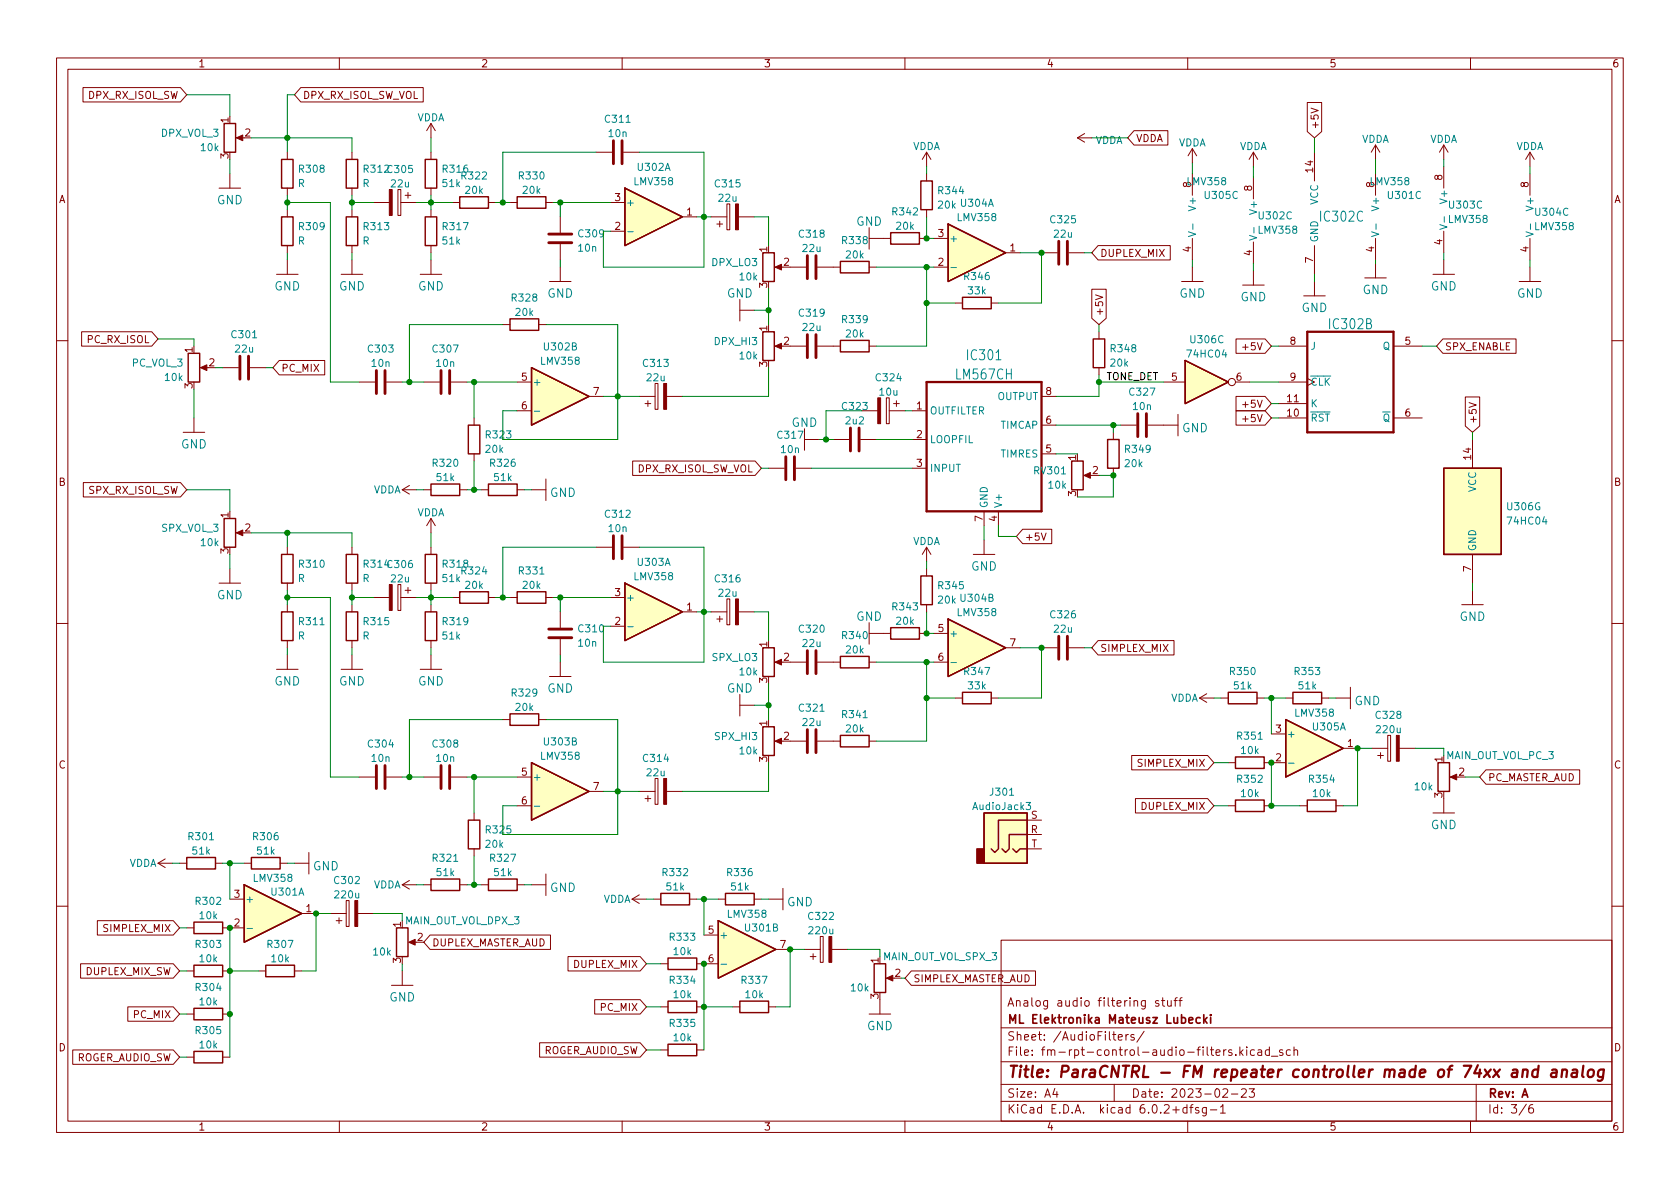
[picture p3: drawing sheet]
<svg xmlns="http://www.w3.org/2000/svg" width="297mm" height="210mm" viewBox="0 0 297 210" stroke-linecap="round" stroke-linejoin="round" font-family="sans-serif">
<defs><g id="words">
<text font-size="2.8" fill="#840000" x="178" y="190.6">Title: ParaCNTRL - FM repeater controller made of 74xx and analog</text>
<g font-size="2.5" fill="#008484">
<text x="233.6" y="39.2">IC302C</text>
<text x="235.2" y="58.2">IC302B</text>
<text x="171.2" y="63.7">IC301</text>
<text x="169.2" y="67.1">LM567CH</text>
</g>
<g font-size="2.1" fill="#008484">
<text x="38.3" y="36.1">GND</text>
<text x="151.4" y="39.9">GND</text>
<text x="48.5" y="51.4">GND</text>
<text x="59.9" y="51.4">GND</text>
<text x="73.9" y="51.4">GND</text>
<text x="96.7" y="52.6">GND</text>
<text x="128.5" y="52.6">GND</text>
<text x="208.5" y="52.6">GND</text>
<text x="219.3" y="53.3">GND</text>
<text x="240.9" y="52">GND</text>
<text x="253" y="51.4">GND</text>
<text x="268.2" y="52.6">GND</text>
<text x="230.1" y="55.2">GND</text>
<text x="139.9" y="75.5">GND</text>
<text x="209" y="76.4">GND</text>
<text x="32" y="79.3">GND</text>
<text x="97.2" y="87.9">GND</text>
<text x="171.7" y="100.9">GND</text>
<text x="38.3" y="106">GND</text>
<text x="151.4" y="109.8">GND</text>
<text x="258" y="109.8">GND</text>
<text x="48.5" y="121.2">GND</text>
<text x="59.9" y="121.2">GND</text>
<text x="73.9" y="121.2">GND</text>
<text x="96.7" y="122.5">GND</text>
<text x="128.5" y="122.5">GND</text>
<text x="239.5" y="124.7">GND</text>
<text x="253" y="146.6">GND</text>
<text x="55.3" y="153.9">GND</text>
<text x="97.2" y="157.7">GND</text>
<text x="139.1" y="160.3">GND</text>
<text x="68.8" y="177.1">GND</text>
<text x="153.3" y="182.2">GND</text>
</g>
<g font-size="2.1" fill="#840000">
<text x="178" y="178">Analog audio filtering stuff</text>
<text x="178" y="184">Sheet: /AudioFilters/</text>
<text x="178" y="181">ML Elektronika Mateusz Lubecki</text>
<text x="178" y="186.7">File: fm-rpt-control-audio-filters.kicad_sch</text>
<text x="178" y="196.9">KiCad E.D.A. kicad 6.0.2+dfsg-1</text>
<text x="178" y="194.1">Size: A4</text>
<text x="200" y="194.1">Date: 2023-02-23</text>
<text x="263" y="194.1">Rev: A</text>
<text x="263" y="196.9">Id: 3/6</text>
</g>
<g font-size="1.8" fill="#840000">
<text x="35" y="11.9">1</text>
<text x="85" y="11.9">2</text>
<text x="135" y="11.9">3</text>
<text x="185" y="11.9">4</text>
<text x="235" y="11.9">5</text>
<text x="285" y="11.9">6</text>
<text x="15.6" y="17.5">DPX_RX_ISOL_SW</text>
<text x="53.5" y="17.5">DPX_RX_ISOL_SW_VOL</text>
<text x="40.4" y="21.7" transform="rotate(-90 40.4 21.7)">1</text>
<text x="233.1" y="22.9" transform="rotate(-90 233.1 22.9)">+5V</text>
<text x="40.4" y="28" transform="rotate(-90 40.4 28)">3</text>
<text x="43.3" y="24.1">2</text>
<text x="200.8" y="25.1">VDDA</text>
<text x="10.3" y="35.9">A</text>
<text x="108.7" y="35.6">3</text>
<text x="210.6" y="33.1" transform="rotate(-90 210.6 33.1)">8</text>
<text x="221.4" y="33.8" transform="rotate(-90 221.4 33.8)">8</text>
<text x="232.2" y="30.4" transform="rotate(-90 232.2 30.4)">14</text>
<text x="243" y="33.1" transform="rotate(-90 243 33.1)">8</text>
<text x="255" y="31.9" transform="rotate(-90 255 31.9)">8</text>
<text x="270.3" y="33.1" transform="rotate(-90 270.3 33.1)">8</text>
<text x="285.3" y="35.9">A</text>
<text x="108.7" y="40.6">2</text>
<text x="121.4" y="38.1">1</text>
<text x="165.9" y="41.9">3</text>
<text x="135.6" y="44.6" transform="rotate(-90 135.6 44.6)">1</text>
<text x="138.6" y="47">2</text>
<text x="165.9" y="47">2</text>
<text x="178.6" y="44.4">1</text>
<text x="194.5" y="45.4">DUPLEX_MIX</text>
<text x="210.6" y="44.6" transform="rotate(-90 210.6 44.6)">4</text>
<text x="221.4" y="45.2" transform="rotate(-90 221.4 45.2)">4</text>
<text x="232.2" y="46.5" transform="rotate(-90 232.2 46.5)">7</text>
<text x="243" y="44.6" transform="rotate(-90 243 44.6)">4</text>
<text x="255" y="43.3" transform="rotate(-90 255 43.3)">4</text>
<text x="270.3" y="44.6" transform="rotate(-90 270.3 44.6)">4</text>
<text x="135.6" y="50.9" transform="rotate(-90 135.6 50.9)">3</text>
<text x="135.6" y="58.5" transform="rotate(-90 135.6 58.5)">1</text>
<text x="195" y="56" transform="rotate(-90 195 56)">+5V</text>
<text x="15.5" y="60.7">PC_RX_ISOL</text>
<text x="34" y="62.3" transform="rotate(-90 34 62.3)">1</text>
<text x="37" y="64.8">2</text>
<text x="49.7" y="65.7">PC_MIX</text>
<text x="135.6" y="64.9" transform="rotate(-90 135.6 64.9)">3</text>
<text x="138.6" y="61">2</text>
<text x="220.2" y="61.9">+5V</text>
<text x="228.1" y="61">8</text>
<text x="248.4" y="61">5</text>
<text x="255.4" y="61.9">SPX_ENABLE</text>
<text x="34" y="68.7" transform="rotate(-90 34 68.7)">3</text>
<text x="92.2" y="67.3">5</text>
<text x="104.9" y="69.8">7</text>
<text x="184.9" y="69.8">8</text>
<text x="207.2" y="67.3">5</text>
<text x="218.6" y="67.3">6</text>
<text x="227.6" y="71.1">11</text>
<text x="228.1" y="67.3">9</text>
<text x="92.2" y="72.4">6</text>
<text x="162.1" y="72.4">1</text>
<text x="162.1" y="77.5">2</text>
<text x="184.9" y="74.9">6</text>
<text x="220.2" y="74.6">+5V</text>
<text x="220.2" y="72.1">+5V</text>
<text x="227.6" y="73.7">10</text>
<text x="248.4" y="73.7">6</text>
<text x="261.1" y="75" transform="rotate(-90 261.1 75)">+5V</text>
<text x="112.5" y="83.5">DPX_RX_ISOL_SW_VOL</text>
<text x="162.1" y="82.5">3</text>
<text x="184.9" y="80">5</text>
<text x="190.2" y="81.4" transform="rotate(-90 190.2 81.4)">1</text>
<text x="193.2" y="83.8">2</text>
<text x="260.1" y="81.2" transform="rotate(-90 260.1 81.2)">14</text>
<text x="10.3" y="85.9">B</text>
<text x="15.7" y="87.3">SPX_RX_ISOL_SW</text>
<text x="190.2" y="87.7" transform="rotate(-90 190.2 87.7)">3</text>
<text x="285.3" y="85.9">B</text>
<text x="40.4" y="91.5" transform="rotate(-90 40.4 91.5)">1</text>
<text x="43.3" y="94">2</text>
<text x="173.7" y="92.2" transform="rotate(-90 173.7 92.2)">7</text>
<text x="176.3" y="92.2" transform="rotate(-90 176.3 92.2)">4</text>
<text x="181.1" y="95.6">+5V</text>
<text x="40.4" y="97.9" transform="rotate(-90 40.4 97.9)">3</text>
<text x="260.1" y="101.1" transform="rotate(-90 260.1 101.1)">7</text>
<text x="108.7" y="105.4">3</text>
<text x="121.4" y="107.9">1</text>
<text x="108.7" y="110.5">2</text>
<text x="165.9" y="111.8">5</text>
<text x="135.6" y="114.4" transform="rotate(-90 135.6 114.4)">1</text>
<text x="138.6" y="116.8">2</text>
<text x="165.9" y="116.8">6</text>
<text x="178.6" y="114.3">7</text>
<text x="194.5" y="115.3">SIMPLEX_MIX</text>
<text x="135.6" y="120.8" transform="rotate(-90 135.6 120.8)">3</text>
<text x="135.6" y="128.4" transform="rotate(-90 135.6 128.4)">1</text>
<text x="138.6" y="130.8">2</text>
<text x="225.6" y="129.5">3</text>
<text x="10.3" y="135.9">C</text>
<text x="92.2" y="137.2">5</text>
<text x="135.6" y="134.7" transform="rotate(-90 135.6 134.7)">3</text>
<text x="201.3" y="135.6">SIMPLEX_MIX</text>
<text x="225.6" y="134.6">2</text>
<text x="238.3" y="132.1">1</text>
<text x="255" y="134.7" transform="rotate(-90 255 134.7)">1</text>
<text x="258" y="137.2">2</text>
<text x="285.3" y="135.9">C</text>
<text x="92.2" y="142.2">6</text>
<text x="104.9" y="139.7">7</text>
<text x="201.9" y="143.2">DUPLEX_MIX</text>
<text x="255" y="141.1" transform="rotate(-90 255 141.1)">3</text>
<text x="263.1" y="138.1">PC_MASTER_AUD</text>
<text x="182.2" y="147.3">R</text>
<text x="182.3" y="144.8">S</text>
<text x="182.3" y="149.9">T</text>
<text x="41.4" y="158.7">3</text>
<text x="54.1" y="161.3">1</text>
<text x="18.4" y="164.8">SIMPLEX_MIX</text>
<text x="41.4" y="163.8">2</text>
<text x="70.9" y="163.9" transform="rotate(-90 70.9 163.9)">1</text>
<text x="73.8" y="166.4">2</text>
<text x="76.4" y="167.3">DUPLEX_MASTER_AUD</text>
<text x="125.2" y="165.1">5</text>
<text x="137.9" y="167.6">7</text>
<text x="15.2" y="172.4">DUPLEX_MIX_SW</text>
<text x="70.9" y="170.3" transform="rotate(-90 70.9 170.3)">3</text>
<text x="101.6" y="171.2">DUPLEX_MIX</text>
<text x="125.2" y="170.2">6</text>
<text x="155.3" y="170.3" transform="rotate(-90 155.3 170.3)">1</text>
<text x="158.3" y="172.7">2</text>
<text x="161.4" y="173.7">SIMPLEX_MASTER_AUD</text>
<text x="106.3" y="178.8">PC_MIX</text>
<text x="155.3" y="176.6" transform="rotate(-90 155.3 176.6)">3</text>
<text x="10.3" y="185.9">D</text>
<text x="23.7" y="180">PC_MIX</text>
<text x="285.3" y="185.9">D</text>
<text x="13.3" y="187.7">ROGER_AUDIO_SW</text>
<text x="95.9" y="186.4">ROGER_AUDIO_SW</text>
<text x="35" y="199.9">1</text>
<text x="85" y="199.9">2</text>
<text x="135" y="199.9">3</text>
<text x="185" y="199.9">4</text>
<text x="235" y="199.9">5</text>
<text x="285" y="199.9">6</text>
</g>
<g font-size="1.8" fill="#008484">
<text x="73.7" y="21.4">VDDA</text>
<text x="107.1" y="21.7">C311</text>
<text x="28.5" y="24.2">DPX_VOL_3</text>
<text x="35.6" y="26.7">10k</text>
<text x="107.7" y="24.2">10n</text>
<text x="161.3" y="26.5">VDDA</text>
<text x="193.6" y="25.4">VDDA</text>
<text x="208.3" y="25.9">VDDA</text>
<text x="219.1" y="26.5">VDDA</text>
<text x="240.7" y="25.2">VDDA</text>
<text x="252.8" y="25.2">VDDA</text>
<text x="268" y="26.5">VDDA</text>
<text x="52.7" y="33.1">R</text>
<text x="53" y="30.5">R308</text>
<text x="64.1" y="33.1">R</text>
<text x="64.4" y="30.5">R312C305</text>
<text x="69.2" y="33.1">22u</text>
<text x="78.3" y="33.1">51k</text>
<text x="78.4" y="30.5">R316</text>
<text x="81.7" y="31.7">R322</text>
<text x="82.3" y="34.3">20k</text>
<text x="91.9" y="31.7">R330</text>
<text x="92.5" y="34.3">20k</text>
<text x="112.2" y="32.7">LMV358</text>
<text x="112.8" y="30.2">U302A</text>
<text x="126.5" y="33.1">C315</text>
<text x="127.1" y="35.7">22u</text>
<text x="166" y="34.3">R344</text>
<text x="210" y="32.7">LMV358</text>
<text x="213.1" y="35.2">U305C</text>
<text x="242.4" y="32.7">LMV358</text>
<text x="245.5" y="35.2">U301C</text>
<text x="255.9" y="35.6" transform="rotate(-90 255.9 35.6)">V+</text>
<text x="53" y="40.7">R309</text>
<text x="64.4" y="40.7">R313</text>
<text x="78.4" y="40.7">R317</text>
<text x="102.4" y="42">C309</text>
<text x="110.6" y="36.4">+</text>
<text x="157.9" y="38.1">R342</text>
<text x="158.5" y="40.6">20k</text>
<text x="165.9" y="36.9">20k U304A</text>
<text x="169.4" y="39.1">LMV358</text>
<text x="185.8" y="39.5">C325</text>
<text x="211.5" y="36.9" transform="rotate(-90 211.5 36.9)">V+</text>
<text x="222.2" y="37.5" transform="rotate(-90 222.2 37.5)">V+</text>
<text x="222.6" y="41.3">LMV358</text>
<text x="222.7" y="38.8">U302C</text>
<text x="233" y="36.2" transform="rotate(-90 233 36.2)">VCC</text>
<text x="243.8" y="36.9" transform="rotate(-90 243.8 36.9)">V+</text>
<text x="256.2" y="39.4">LMV358</text>
<text x="256.3" y="36.9">U303C</text>
<text x="271.1" y="36.9" transform="rotate(-90 271.1 36.9)">V+</text>
<text x="271.5" y="40.7">LMV358</text>
<text x="271.6" y="38.1">U304C</text>
<text x="52.7" y="43.2">R</text>
<text x="64.1" y="43.2">R</text>
<text x="78.3" y="43.2">51k</text>
<text x="102.3" y="44.5">10n</text>
<text x="125.9" y="47">DPX_LO3</text>
<text x="141.4" y="42">C318</text>
<text x="142" y="44.6">22u</text>
<text x="149" y="43.2">R338</text>
<text x="149.7" y="45.7">20k</text>
<text x="167.8" y="42.8">+</text>
<text x="186.4" y="42">22u</text>
<text x="233" y="42.9" transform="rotate(-90 233 42.9)">GND</text>
<text x="90.6" y="53.3">R328</text>
<text x="130.8" y="49.6">10k</text>
<text x="170.6" y="49.5">R346</text>
<text x="171.2" y="52">33k</text>
<text x="41.1" y="59.8">C301</text>
<text x="91.2" y="55.9">20k</text>
<text x="141.4" y="56">C319</text>
<text x="142" y="58.5">22u</text>
<text x="149" y="57.1">R339</text>
<text x="149.7" y="59.7">20k</text>
<text x="23.3" y="64.8">PC_VOL_3</text>
<text x="41.7" y="62.3">22u</text>
<text x="65.2" y="62.3">C303</text>
<text x="65.8" y="64.9">10n</text>
<text x="76.6" y="62.3">C307</text>
<text x="77.2" y="64.9">10n</text>
<text x="95.7" y="64.5">LMV358</text>
<text x="96.3" y="62">U302B</text>
<text x="113.8" y="64.9">C313</text>
<text x="126.4" y="61">DPX_HI3</text>
<text x="130.8" y="63.5">10k</text>
<text x="196.4" y="64.8">20k</text>
<text x="196.5" y="62.3">R348</text>
<text x="210.1" y="63.2">74HC04</text>
<text x="210.6" y="60.7">U306C</text>
<text x="231.6" y="61.8">J</text>
<text x="244.5" y="61.8">Q</text>
<text x="29.2" y="67.4">10k</text>
<text x="94.1" y="68.2">+</text>
<text x="114.4" y="67.4">22u</text>
<text x="155" y="67.4">C324</text>
<text x="155.6" y="70">10u</text>
<text x="176.4" y="70.7">OUTPUT</text>
<text x="199.8" y="70">C327</text>
<text x="231.6" y="68.2">~{CLK}</text>
<text x="86" y="77.5">R323</text>
<text x="137.6" y="77.6">C317</text>
<text x="149" y="72.5">C323</text>
<text x="149.6" y="75">2u2</text>
<text x="164.3" y="73.3">OUTFILTER</text>
<text x="176.9" y="75.8">TIMCAP</text>
<text x="200.4" y="72.5">10n</text>
<text x="231.6" y="74.5">~{RST}</text>
<text x="231.6" y="72">K</text>
<text x="243.1" y="74.5">~{Q}</text>
<text x="76.6" y="82.5">R320</text>
<text x="85.9" y="80.1">20k</text>
<text x="86.8" y="82.5">R326</text>
<text x="138.2" y="80.1">10n</text>
<text x="164.3" y="78.4">LOOPFIL</text>
<text x="164.3" y="83.4">INPUT</text>
<text x="177" y="80.9">TIMRES</text>
<text x="182.9" y="83.9">RV301</text>
<text x="199" y="82.6">20k</text>
<text x="199" y="80.1">R349</text>
<text x="66" y="87.2">VDDA</text>
<text x="77.3" y="85.1">51k</text>
<text x="87.4" y="85.1">51k</text>
<text x="174.6" y="89.9" transform="rotate(-90 174.6 89.9)">GND</text>
<text x="177.2" y="89.9" transform="rotate(-90 177.2 89.9)">V+</text>
<text x="185.4" y="86.4">10k</text>
<text x="261" y="87" transform="rotate(-90 261 87)">VCC</text>
<text x="28.6" y="94">SPX_VOL_3</text>
<text x="73.7" y="91.3">VDDA</text>
<text x="107.1" y="91.5">C312</text>
<text x="107.7" y="94.1">10n</text>
<text x="266.6" y="90.2">U306G</text>
<text x="266.7" y="92.8">74HC04</text>
<text x="35.6" y="96.6">10k</text>
<text x="53" y="100.4">R310</text>
<text x="64.4" y="100.4">R314C306</text>
<text x="78.4" y="100.4">R318</text>
<text x="81.7" y="101.6">R324</text>
<text x="91.9" y="101.6">R331</text>
<text x="112.8" y="100.1">U303A</text>
<text x="161.3" y="96.4">VDDA</text>
<text x="261" y="97.5" transform="rotate(-90 261 97.5)">GND</text>
<text x="52.7" y="102.9">R</text>
<text x="64.1" y="102.9">R</text>
<text x="69.2" y="103">22u</text>
<text x="78.3" y="102.9">51k</text>
<text x="82.3" y="104.1">20k</text>
<text x="92.5" y="104.1">20k</text>
<text x="110.6" y="106.3">+</text>
<text x="112.2" y="102.6">LMV358</text>
<text x="126.5" y="103">C316</text>
<text x="127.1" y="105.5">22u</text>
<text x="157.9" y="107.9">R343</text>
<text x="165.9" y="106.7">20k U304B</text>
<text x="166" y="104.2">R345</text>
<text x="52.7" y="113.1">R</text>
<text x="53" y="110.5">R311</text>
<text x="64.1" y="113.1">R</text>
<text x="64.4" y="110.5">R315</text>
<text x="78.3" y="113.1">51k</text>
<text x="78.4" y="110.5">R319</text>
<text x="102.4" y="111.8">C310</text>
<text x="141.4" y="111.9">C320</text>
<text x="149" y="113">R340</text>
<text x="158.5" y="110.5">20k</text>
<text x="167.8" y="112.6">+</text>
<text x="169.4" y="108.9">LMV358</text>
<text x="185.8" y="109.3">C326</text>
<text x="186.4" y="111.9">22u</text>
<text x="102.3" y="114.3">10n</text>
<text x="125.9" y="116.9">SPX_LO3</text>
<text x="130.8" y="119.4">10k</text>
<text x="142" y="114.4">22u</text>
<text x="149.7" y="115.5">20k</text>
<text x="170.6" y="119.4">R347</text>
<text x="217.6" y="119.4">R350</text>
<text x="229" y="119.4">R353</text>
<text x="90.6" y="123.2">R329</text>
<text x="91.2" y="125.7">20k</text>
<text x="141.4" y="125.8">C321</text>
<text x="171.2" y="121.9">33k</text>
<text x="206.9" y="124.1">VDDA</text>
<text x="218.2" y="121.9">51k</text>
<text x="229.7" y="121.9">51k</text>
<text x="96.3" y="131.8">U303B</text>
<text x="126.5" y="130.9">SPX_HI3</text>
<text x="142" y="128.4">22u</text>
<text x="149" y="127">R341</text>
<text x="149.7" y="129.5">20k</text>
<text x="218.9" y="130.8">R351</text>
<text x="227.5" y="130.4">+</text>
<text x="229.1" y="126.7">LMV358</text>
<text x="232.2" y="129.2">U305A</text>
<text x="243.4" y="127.1">C328</text>
<text x="243.5" y="129.6">220u</text>
<text x="65.2" y="132.2">C304</text>
<text x="65.8" y="134.7">10n</text>
<text x="76.6" y="132.2">C308</text>
<text x="77.2" y="134.7">10n</text>
<text x="95.7" y="134.3">LMV358</text>
<text x="113.8" y="134.7">C314</text>
<text x="114.4" y="137.3">22u</text>
<text x="130.8" y="133.4">10k</text>
<text x="219.5" y="133.3">10k</text>
<text x="94.1" y="138">+</text>
<text x="172.2" y="143.2">AudioJack3</text>
<text x="175.2" y="140.7">J301</text>
<text x="218.9" y="138.4">R352</text>
<text x="219.5" y="140.9">10k</text>
<text x="231.6" y="138.4">R354</text>
<text x="232.2" y="140.9">10k</text>
<text x="250.2" y="139.7">10k</text>
<text x="33.4" y="148.6">R301</text>
<text x="44.9" y="148.6">R306</text>
<text x="85.9" y="149.9">20k</text>
<text x="86" y="147.4">R325</text>
<text x="22.8" y="153.3">VDDA</text>
<text x="34.1" y="151.1">51k</text>
<text x="44.9" y="155.9">LMV358</text>
<text x="45.5" y="151.1">51k</text>
<text x="76.6" y="152.4">R321</text>
<text x="77.3" y="154.9">51k</text>
<text x="86.8" y="152.4">R327</text>
<text x="87.4" y="154.9">51k</text>
<text x="117.3" y="154.9">R332</text>
<text x="128.7" y="154.9">R336</text>
<text x="34.7" y="160">R302</text>
<text x="43.3" y="159.6">+</text>
<text x="48" y="158.4">U301A</text>
<text x="59.2" y="156.3">C302</text>
<text x="59.3" y="158.9">220u</text>
<text x="66" y="157.1">VDDA</text>
<text x="106.6" y="159.6">VDDA</text>
<text x="117.9" y="157.5">51k</text>
<text x="129.3" y="157.5">51k</text>
<text x="34.7" y="167.6">R303</text>
<text x="35.4" y="162.5">10k</text>
<text x="47.4" y="167.6">R307</text>
<text x="118.5" y="166.3">R333</text>
<text x="127.1" y="166">+</text>
<text x="128.7" y="162.3">LMV358</text>
<text x="131.9" y="164.7">U301B</text>
<text x="143" y="162.7">C322</text>
<text x="143.1" y="165.2">220u</text>
<text x="35.4" y="170.2">10k</text>
<text x="48.1" y="170.2">10k</text>
<text x="66.1" y="169">10k</text>
<text x="118.5" y="174">R334</text>
<text x="119.2" y="168.9">10k</text>
<text x="131.2" y="174">R337</text>
<text x="156.1" y="169.8">MAIN_OUT_VOL_SPX_3</text>
<text x="34.7" y="175.2">R304</text>
<text x="35.4" y="177.8">10k</text>
<text x="119.2" y="176.5">10k</text>
<text x="131.9" y="176.5">10k</text>
<text x="150.5" y="175.3">10k</text>
<text x="34.7" y="182.9">R305</text>
<text x="35.4" y="185.4">10k</text>
<text x="118.5" y="181.6">R335</text>
<text x="119.2" y="184.1">10k</text>
</g>
<text font-size="1.8" x="195.6" y="67.2">TONE_DET</text>
<g font-size="1.8" fill="#008400">
<text x="255.7" y="134.2">MAIN_OUT_VOL_PC_3</text>
<text x="71.6" y="163.4">MAIN_OUT_VOL_DPX_3</text>
</g>
</g></defs>
<g fill="none" stroke="#840000" stroke-width=".18">
<path d="M10 10.2h277v190.1h-277zM12 12.2h273v186.1h-273zM14.7 15.5h17.2l1.1 1.3-1.1 1.2h-17.2zM53.2 15.5h21.6v2.5h-21.6l-1.1-1.2zM60 10.2v2M110 10.2v2M160 10.2v2M210 10.2v2M231.1 18.1h2.6v5.2l-1.3 1.1-1.3-1.1zM231.8 19.1l1.3 .4-1.3 .5M260 10.2v2M38.7 33.3h3.8"/>
<path d="M40.6 30.7v2.6M42.2 24.4h1M50.8 26.9v1.3M50.8 33.3v1.2M50.8 37.1v1.2M62.2 26.9v1.3M62.2 33.3v1.2M62.2 37.1v1.2M66 35.8h2.8M70.4 33.5h.5v4.6h-.5zM70.9 35.8h2.8M71.6 34.5h1"/>
<path d="M72.1 34v1M76.2 21.8v2.6M76.2 26.9v1.3M76.2 33.3v1.2M76.2 37.1v1.2M76.2 21.8l-.8 1.3M76.2 21.8l.8 1.3M80 35.8h1.3M86.4 35.8h1.2M90.2 35.8h1.2M96.5 35.8h1.3M99.1 38.3v2.8"/>
<path d="M105.4 26.9h2.8M107.9 35.8h2.6M110.2 26.9h2.8M120.6 38.3h2.6M125.7 38.3h2.8M126.7 39.6h1.1M127.3 39.1v1M128.5 36.1h.5v4.5h-.5zM130.6 38.3h2.7M163.8 26.9v2.6M163.8 30.7v1.3M163.8 37.1v1.2"/>
<path d="M163.8 26.9l-.7 1.3M163.8 26.9l.8 1.3M190.5 24.4l1.3 .7M190.5 24.4h2.5M191.8 23.6l-1.3 .8M200.5 23.1h6v2.5h-6l-1.1-1.2zM210.8 26.3v2.5M210.8 30.7v3.8M210.8 26.3l-.7 1.3M210.8 26.3l.8 1.3M221.6 26.9v2.6M221.6 31.4v3.8"/>
<path d="M221.6 26.9l-.7 1.3M221.6 26.9l.8 1.3M232.4 26.9v5.1M243.2 25.6v2.6M243.2 30.7v3.8M243.2 25.6l-.8 1.3M243.2 25.6l.8 1.3M255.3 25.6l-.8 1.3M255.3 25.6v2.6M255.3 29.5v3.8M255.3 25.6l.7 1.3M270.5 26.9v2.6"/>
<path d="M270.5 30.7v3.8M270.5 26.9l-.8 1.3M270.5 26.9l.8 1.3M14.4 58.7h12.4l1.1 1.2-1.1 1.3h-12.4zM48.9 48.5h3.8M50.8 43.4v1.3M50.8 46v2.5M60.3 48.5h3.8M62.2 43.4v1.3M62.2 46v2.5M74.3 48.5h3.8M76.2 43.4v1.3"/>
<path d="M76.2 46v2.5M88.9 57.4h1.3M95.2 57.4h1.3M97.2 49.8h3.8M99.1 43.2v2.8M99.1 47.2v2.6M107.9 40.9h2.6M130.8 53v3.8M130.8 54.9h2.5M137.4 47.2h1M139.7 47.2h2.8M144.5 47.2h4.1"/>
<path d="M153.7 40.3v3.8M153.7 47.2h1.2M153.7 42.2h3.8M162.6 42.2h1.2M165.1 47.2h2.5M165.1 42.2h2.5M168.9 53.6h1.3M175.3 53.6h1.2M177.8 44.7h2.5M184.1 44.7h2.8M189 44.7h2.8M193 51.1h2.6v5.2l-1.3 1.1-1.3-1.1z"/>
<path d="M193.7 52.1l1.3 .5-1.3 .4M194.2 43.4h12.7v2.6h-12.7l-1.2-1.3zM194.3 58.7v1.2M208.9 49.8h3.8M210.8 42.2v3.8M210.8 47.2v2.6M218.5 59.9h5.2l1.1 1.3-1.1 1.3h-5.2zM219.7 50.4h3.8M221.6 42.8v3.8M221.6 47.9v2.5M230.5 52.3h3.8M232.4 43.4v5.1"/>
<path d="M232.4 49.8v2.5M241.3 49.1h3.8M243.2 42.2v3.8M243.2 46.6v2.5M253.4 48.5h3.8M255.1 59.9h13v2.6h-13l-1.1-1.3zM255.3 40.9v3.8M255.3 46v2.5M268.6 49.8h3.8M270.5 42.2v3.8M270.5 47.2v2.6M10 60.2h2"/>
<path d="M32.4 76.4h3.8M34.3 73.9v2.5M35.8 65h1M39.4 65h2.8M44.2 65h2.8M49.4 63.7h8v2.6h-8l-1.1-1.3zM63.5 67.6h2.8M68.3 67.6h2.8M74.9 67.6h2.8M79.8 67.6h2.7M83.8 73.9v1.3M91.4 67.6h2.6"/>
<path d="M91.4 72.6h2.6M104.1 70.1h2.6M113 70.1h2.8M114 71.4h1.1M114.6 70.9v1M115.8 67.8h.5v4.6h-.5zM117.9 70.1h2.7M137.4 61.2h1M139.7 61.2h2.8M142.2 77.7h2.6M142.2 75.8v3.8M144.5 61.2h4.1"/>
<path d="M147.3 77.7h2.8M152.1 77.7h2.8M152.4 72.6h2.8M153.7 61.2h1.2M156.7 70.4h.5v4.5h-.5zM157.2 72.6h2.8M158 71.4h1M158.5 70.9v1M161.3 72.6h2.5M161.3 77.7h2.5M184.1 75.2h2.6M184.1 70.1h2.6"/>
<path d="M194.3 65v1.3M196.8 76.4v1.3M198.1 75.2h2.8M202.9 75.2h5.4M205.7 67.6h3.8M208.3 73.3v3.8M218.4 67.6h2.6M218.5 72.6h5.2l1.1 1.3-1.1 1.3h-5.2zM218.5 70.1h5.2l1.1 1.3-1.1 1.2h-5.2zM226.1 67.6h5M226.1 73.9h5M226.1 71.4h5"/>
<path d="M226.1 61.2h5M246.4 73.9h5.1M246.4 61.2h5.1M259.1 70.2h2.5v5.1l-1.3 1.1-1.2-1.1zM259.7 71.2l1.3 .4-1.3 .4M260.3 77.7v5.1M285 60.2h2M14.7 85.3h17.2l1.1 1.3-1.1 1.3h-17.2zM42.2 94.2h1M50.8 96.8v1.2M62.2 96.8v1.2M71.1 86.6h2.6"/>
<path d="M71.1 86.6l1.3 .8M72.4 85.8l-1.3 .8M74.9 86.6h1.3M76.2 91.7v2.5M76.2 96.8v1.2M76.2 91.7l-.8 1.3M76.2 91.7l.8 1.3M81.3 86.6h1.2M83.8 80.3v1.2M85.1 86.6h1.3M91.4 86.6h1.3M94 86.6h2.5"/>
<path d="M96.5 84.7v3.8M105.4 96.8h2.8M110.2 96.8h2.8M111.9 81.5h21.6l1.1 1.3-1.1 1.3h-21.6zM135.9 82.8h2.8M140.7 82.8h2.8M161.3 82.8h2.5M163.8 96.8v2.5M163.8 96.8l-.7 1.2M163.8 96.8l.8 1.2M172.1 98h3.8M174 90.4v2.6"/>
<path d="M174 95.5v2.5M176.5 90.4v2.6M180.8 93.6h5.2v2.5h-5.2l-1.1-1.2zM184.1 94.3l.4 1.2 .5-1.2M184.1 80.3h2.6M192 84.1h1M196.8 82.8v1.3M260.3 98v5.1M10 110.2h2M38.7 103.1h3.8M40.6 100.6v2.5M48.9 118.4h3.8"/>
<path d="M50.8 103.1v1.3M50.8 106.9v1.3M50.8 113.3v1.2M50.8 115.8v2.6M60.3 118.4h3.8M62.2 103.1v1.3M62.2 106.9v1.3M62.2 113.3v1.2M62.2 115.8v2.6M66 105.7h2.8M70.4 103.4h.5v4.5h-.5zM70.9 105.7h2.8"/>
<path d="M71.6 104.4h1M72.1 103.9v1M74.3 118.4h3.8M76.2 103.1v1.3M76.2 106.9v1.3M76.2 113.3v1.2M76.2 115.8v2.6M80 105.7h1.3M86.4 105.7h1.2M90.2 105.7h1.2M96.5 105.7h1.3M97.2 119.6h3.8"/>
<path d="M99.1 108.2v2.8M99.1 113v2.8M99.1 117.1v2.5M107.9 105.7h2.6M107.9 110.7h2.6M120.6 108.2h2.6M125.7 108.2h2.8M126.7 109.5h1.1M127.3 109v1M128.5 105.9h.5v4.6h-.5zM130.6 108.2h2.7M137.4 117.1h1"/>
<path d="M139.7 117.1h2.8M144.5 117.1h4.1M153.7 112h3.8M153.7 117.1h1.2M153.7 110.1v3.8M162.6 112h1.2M163.8 100.6v1.2M163.8 106.9v1.3M165.1 112h2.5M165.1 117.1h2.5M177.8 114.5h2.5M184.1 114.5h2.8"/>
<path d="M189 114.5h2.8M194.2 113.3h13.4v2.5h-13.4l-1.2-1.3zM258.4 106.9h3.9M260.3 104.4v2.5M285 110.2h2M63.5 137.4h2.8M68.3 137.4h2.8M74.9 137.4h2.8M79.8 137.4h2.7M88.9 127.2h1.3M91.4 137.4h2.6M95.2 127.2h1.3"/>
<path d="M104.1 139.9h2.6M113 139.9h2.8M115.8 137.7h.5v4.5h-.5zM117.9 139.9h2.7M130.8 122.8v3.8M130.8 124.7h2.5M137.4 131.1h1M139.7 131.1h2.8M144.5 131.1h4.1M153.7 131.1h1.2M168.9 123.4h1.3M175.3 123.4h1.2"/>
<path d="M200.1 133.6h13.4l1.1 1.3-1.1 1.2h-13.4zM212.1 123.4h2.5M212.1 123.4l1.3 .8M213.4 122.7l-1.3 .7M215.9 123.4h1.3M217.2 134.9h1.2M222.2 123.4h1.3M223.5 134.9h3.8M224.8 129.8h2.5M227.3 123.4h1.3M233.7 123.4h1.2M236.2 123.4h2.6"/>
<path d="M237.5 132.3h2.5M238.8 121.5v3.8M242.6 132.3h2.8M243.6 133.6h1M244.1 133.1v1M245.4 130h.5v4.6h-.5zM247.4 132.3h2.8M256.8 137.4h1M262.7 136.1h16.6v2.6h-16.6l-1.1-1.3zM27.9 152.6h2.6M27.9 152.6l1.3 .8M29.2 151.9l-1.3 .7"/>
<path d="M31.7 152.6h1.3M38.1 152.6h1.3M40.6 159h2.6M43.2 152.6h1.2M49.5 152.6h1.3M52.1 152.6h2.5M54.6 150.7v3.9M61.2 159.3h.5v4.5h-.5zM71.1 156.5h2.6M71.1 156.5l1.3 .7M72.4 155.7l-1.3 .8M74.9 156.5h1.3"/>
<path d="M81.3 156.5h1.2M83.8 143.8v1.2M83.8 150.1v1.3M85.1 156.5h1.3M91.4 142.5h2.6M91.4 156.5h1.3M94 156.5h2.5M96.5 154.6v3.8M111.8 159l1.2 .8M111.8 159h2.5M113 158.2l-1.2 .8M114 141.2h1.1"/>
<path d="M114.6 140.7v1M115.6 159h1.2M121.9 159h1.3M127 159h1.3M133.3 159h1.3M135.9 159h2.5M138.4 157.1v3.8M181.6 147.6h2.5M181.6 145h2.5M181.6 150.1h2.5M200.8 141.2h12.7l1.1 1.3-1.1 1.3h-12.7zM217.2 142.5h1.2"/>
<path d="M223.5 142.5h1.3M229.9 142.5h1.2M236.2 142.5h1.3M253.4 143.8h3.8M255.3 141.2v2.6M10 160.2h2M14.2 170.4h16.4l1.1 1.3-1.1 1.3h-16.4zM17.2 162.8h13.4l1.1 1.3-1.1 1.2h-13.4zM22.6 178h8l1.1 1.3-1.1 1.3h-8zM33 179.3h1.3M33 171.7h1.3M33 164.1h1.3"/>
<path d="M39.4 179.3h1.2M39.4 171.7h1.2M39.4 164.1h3.8M45.7 171.7h1.3M52.1 171.7h1.2M53.3 161.5h2.6M58.4 161.5h2.8M59.4 162.8h1.1M59.9 162.3v1M63.2 161.5h2.8M69.2 174.2h3.8M71.1 171.7v2.5"/>
<path d="M72.6 166.6h1.1M76 165.3h21.3v2.6h-21.3l-1.1-1.3zM100.4 169.2h12.8l1.1 1.2-1.1 1.3h-12.8zM105.1 176.8h8.1l1.1 1.2-1.1 1.3h-8.1zM116.8 170.4h1.3M116.8 178h1.3M123.2 170.4h3.8M123.2 178h1.3M124.5 165.3h2.5M129.5 178h1.3M135.9 178h1.3M137.2 167.9h2.5"/>
<path d="M142.2 167.9h2.8M143.3 169.2h1M143.8 168.7v1M145 165.6h.5v4.6h-.5zM147.1 167.9h2.8M153.7 179.3h3.8M155.6 176.8v2.5M157.1 173h1M161.1 171.7h22v2.5h-22l-1.1-1.2zM177 166.3h108v32h-108zM204.9 177l-.4-.1-.2 .2 .1 .3 .5 .1v.4h-.6M205.4 176.9h.5"/>
<path d="M205.6 176.4v1.3l.3 .2M206.4 176.9l.1 1h.4l.2-.1M207.1 176.9v1M207.6 176.9h.5M208.1 176.4l-.3 .2v1.3M208.4 176.9h.6M209 176.4l-.4 .2v1.3M285 160.2h2M12.9 185.7h17.7l1.1 1.2-1.1 1.3h-17.7zM33 186.9h1.3M39.4 186.9h1.2M60 198.3v2"/>
<path d="M95.4 184.4h17.8l1.1 1.3-1.1 1.2h-17.8zM110 198.3v2M116.8 185.7h1.3M123.2 185.7h1.3M160 198.3v2M177 194.8h108M177 191.8h108M177 187.8h108M177 181.8h108M186.5 192.5l-.4 1h1M186.9 193v1M197 191.8v3"/>
<path d="M197.7 183.4l.7-.1v-.3l-.5-.1-.2 .2 .1 .8h.6M199.1 182.9v1M199.5 182.9l-.3 .1-.1 .2M200.5 183l-.4-.1-.2 .2 .1 .3 .5 .1v.4h-.6M202.3 182.4l-1.3 1.9M209.9 195.9l-.5-.1-.3 .3v.4l.2 .3h.6M209.9 195.3v1.5M210 198.3v2M210.4 195.8h.5M210.9 195.3l-.3 .2v1.3M211.9 195.9l-.3-.1-.2 .2v.3l.5 .1v.4h-.5M213.3 195.8v1.2l-.3 .3h-.4"/>
<path d="M213.3 195.9l-.4-.1-.3 .3v.4l.1 .3h.6M214 196.3h1.1M215.8 195.8l.4-.5v1.5M215.8 196.8h.8M216.2 192.7l.6-.2 .2 .2 .1 .3-1 1h1M217.7 193.5h1.2M217.8 185.7l-.4-.1-.2 .2 .1 .3 .5 .1v.4h-.6M218.5 186.5v.1M219.2 185.1v1.5M219.4 186.1l.4 .5M219.5 192.7l.6-.2 .2 .2 .1 .3-1 1h1M219.8 185.6l-.6 .6"/>
<path d="M220.4 185.1v.2M220.4 185.6v1M220.9 192.5h.9l-.5 .6 .4 .1v.7l-.2 .1h-.4l-.2-.1M221.8 185.7l-.4-.1-.3 .3v.4l.1 .3h.6M222.4 185.7h.6l.1 .9M223.1 186l-.5 .1a.29 .29 0 0 0-.2 .2 .29 .29 0 0 0 .2 .3h.5M224.4 185.7l-.4-.1-.3 .3v.4l.2 .3h.5M224.4 185.1v1.5M224.8 186.8h1.1M226.8 185.7l-.4-.1-.2 .2 .1 .3 .5 .1v.4h-.6M228.1 185.7l-.4-.1-.3 .3v.4l.2 .3h.5M228.8 185.8l.2-.2 .4 .1v.9"/>
<path d="M228.8 185.1v1.5M260 198.3v2M261 191.8v6.5M269.9 195.3l-1.3 1.9M271 195.3a.6 .6 0 0 0-.7 .7v.5l.1 .3h.5l.2-.1 .1-.5-.2-.2-.4-.1-.3 .3"/>
<circle cx="217.8" cy="67.6" r=".63"/>
</g>
<g fill="none" stroke="#840000" stroke-width=".4">
<path d="M267.5 189.2l.2-.1 .5 .1v1.3M268.3 189.6l-.7 .1a.4 .4 0 0 0-.3 .3 .4 .4 0 0 0 .2 .5l.7-.1M269.3 189.3a.49 .49 0 0 1 .8 .1l-.1 1.1M269.3 189.1l-.2 1.4M272 189.2a.66 .66 0 0 0-1 .3l-.1 .6 .1 .3 .2 .1 .6-.1M272 188.5l-.2 2M274.4 189.2l.2-.1 .6 .1-.1 1.3M275.2 189.6l-.6 .1a.4 .4 0 0 0-.4 .3 .4 .4 0 0 0 .3 .5l.6-.1M276.2 189.3a.49 .49 0 0 1 .9 .1l-.2 1.1M276.3 189.1l-.2 1.4M278 189.2l.2-.1 .6 .1-.1 1.3M278.9 189.6l-.7 .1a.4 .4 0 0 0-.4 .3 .4 .4 0 0 0 .3 .5l.7-.1"/>
<path d="M280 188.5l-.3 1.7 .3 .3M280.9 189.3a.52 .52 0 0 1 .5-.2 .52 .52 0 0 1 .4 .4l-.1 .6a.55 .55 0 0 1-.5 .4 .55 .55 0 0 1-.5-.4zM283.6 189.2a.66 .66 0 0 0-1 .3l-.1 .6 .2 .3 .1 .1 .6-.1M283.6 189.1l-.2 1.6a.6 .6 0 0 1-.9 .3"/>
</g>
<path d="M212.8 179.4v1.5M213.4 179.9l-.6 .6M214.1 179.4v.2M214.1 179.9v1M210.2 180.4l.7-.1-.1-.3-.4-.1-.2 .2 .1 .8h.5M212.2 180l-.4-.1-.3 .3v.4l.1 .3h.6M213 180.4l.4 .5" fill="none" stroke="#840000" stroke-width=".3"/>
<g fill="none" stroke="#840000" stroke-width=".25">
<path d="M39.6 21.8h2.1v5.1h-2.1zM49.8 38.3h2v5.1h-2zM49.8 28.2h2v5.1h-2zM61.2 28.2h2v5.1h-2zM61.2 38.3h2v5.1h-2zM75.2 38.3h2v5.1h-2zM75.2 28.2h2v5.1h-2zM81.3 34.8h5.1v2h-5.1zM91.4 34.8h5.1v2h-5.1zM110.5 33.3l10.1 5-10.1 5.1zM162.8 32h2v5.1h-2zM167.6 39.6l10.2 5.1-10.2 5.1z"/>
<path d="M90.2 56.4h5v2h-5zM134.9 44.7h2v5.1h-2zM134.9 58.7h2v5h-2zM148.6 46.2h5.1v2.1h-5.1zM157.5 41.1h5.1v2.1h-5.1zM170.2 52.6h5.1v2h-5.1zM193.3 59.9h2v5.1h-2zM33.3 62.5h2v5.1h-2zM82.8 75.2h2v5.1h-2zM94 65l10.1 5.1-10.1 5.1zM148.6 60.2h5.1v2h-5.1zM195.8 77.7h2.1v5.1h-2.1z"/>
<path d="M209.5 63.7l7.7 3.9-7.7 3.8zM39.6 91.7h2.1v5.1h-2.1zM49.8 98h2v5.1h-2zM61.2 98h2v5.1h-2zM75.2 98h2v5.1h-2zM76.2 85.6h5.1v2h-5.1zM86.4 85.6h5v2h-5zM189.5 81.5h2v5.1h-2zM255.3 82.8h10.1v15.2h-10.1zM49.8 108.2h2v5.1h-2zM61.2 108.2h2v5.1h-2zM75.2 108.2h2v5.1h-2z"/>
<path d="M81.3 104.6h5.1v2.1h-5.1zM91.4 104.6h5.1v2.1h-5.1zM110.5 103.1l10.1 5.1-10.1 5.1zM134.9 114.5h2v5.1h-2zM148.6 116.1h5.1v2h-5.1zM157.5 111h5.1v2h-5.1zM162.8 101.8h2v5.1h-2zM167.6 109.5l10.2 5-10.2 5.1zM90.2 126.2h5v2.1h-5zM94 134.9l10.1 5-10.1 5.1zM134.9 128.5h2v5.1h-2zM148.6 130h5.1v2.1h-5.1z"/>
<path d="M170.2 122.4h5.1v2.1h-5.1zM217.2 122.4h5v2.1h-5zM218.4 133.9h5.1v2h-5.1zM227.3 127.2l10.2 5.1-10.2 5.1zM228.6 122.4h5.1v2.1h-5.1zM254.3 134.9h2v5h-2zM33 151.6h5.1v2.1h-5.1zM43.2 156.5l10.1 5-10.1 5.1zM44.4 151.6h5.1v2.1h-5.1zM76.2 155.4h5.1v2.1h-5.1zM82.8 145h2v5.1h-2zM86.4 155.4h5v2.1h-5z"/>
<path d="M116.8 158h5.1v2h-5.1zM128.3 158h5v2h-5zM174 143.8h7.6v8.8h-7.6zM179.1 150.1l.6 .6 .6-.6h1.3M181.6 147.6h-3.2v2.5l-.6 .6-.6-.6M181.6 145h-5.1v5.1l-.6 .6-.6-.6M218.4 141.5h5.1v2h-5.1zM231.1 141.5h5.1v2h-5.1zM34.3 170.7h5.1v2h-5.1zM34.3 178.3h5.1v2h-5.1zM34.3 163.1h5.1v2h-5.1zM47 170.7h5.1v2h-5.1z"/>
<path d="M70.1 164.1h2v5.1h-2zM118.1 169.4h5.1v2h-5.1zM118.1 177h5.1v2.1h-5.1zM127 162.8l10.2 5.1-10.2 5.1zM130.8 177h5.1v2.1h-5.1zM154.6 170.4h2v5.1h-2zM34.3 185.9h5.1v2.1h-5.1zM118.1 184.7h5.1v2h-5.1z"/>
</g>
<g fill="#ffffc2" stroke="#ffffc2" stroke-width=".18">
<path d="M209.5 63.7l7.7 3.9-7.7 3.8z"/>
<path d="M255.3 82.8h10.1v15.2h-10.1z"/>
<path d="M167.6 109.5l10.2 5-10.2 5.1z"/>
<path d="M94 134.9l10.1 5-10.1 5.1z"/>
<path d="M110.5 103.1l10.1 5.1-10.1 5.1z"/>
<path d="M127 162.8l10.2 5.1-10.2 5.1z"/>
<path d="M94 65l10.1 5.1-10.1 5.1z"/>
<path d="M174 143.8h7.6v8.8h-7.6z"/>
<path d="M110.5 33.3l10.1 5-10.1 5.1z"/>
<path d="M227.3 127.2l10.2 5.1-10.2 5.1z"/>
<path d="M43.2 156.5l10.1 5-10.1 5.1z"/>
<path d="M167.6 39.6l10.2 5.1-10.2 5.1z"/>
</g>
<g fill="none" stroke="#840000" stroke-width=".51">
<path d="M108.5 24.9v4.1M110 24.9v4.1M97 41.4h4.1M97 42.9h4.1M142.7 45.2v4.1M142.7 59.2v4M144.3 45.2v4.1M144.3 59.2v4M187.2 42.7v4M188.7 42.7v4M42.4 63v4.1M43.9 63v4.1"/>
<path d="M66.5 65.5v4.1M68.1 65.5v4.1M78 65.5v4.1M79.5 65.5v4.1M150.4 75.7v4.1M151.9 75.7v4.1M201.2 73.1v4.1M202.7 73.1v4.1M108.5 94.7v4.1M110 94.7v4.1M138.9 80.8v4M140.5 80.8v4"/>
<path d="M97 111.2h4.1M97 112.8h4.1M142.7 115.1v4M144.3 115.1v4M187.2 112.5v4.1M188.7 112.5v4.1M66.5 135.4v4M68.1 135.4v4M78 135.4v4M79.5 135.4v4M142.7 129v4.1M144.3 129v4.1"/>
</g>
<g fill="#840000" stroke="#840000" stroke-width=".18">
<path d="M35.4 65l1.2-.5v1z"/>
<path d="M68.8 33.5h.5v4.6h-.5z"/>
<path d="M191.6 84.1l1.2-.5v1z"/>
<path d="M41.8 24.4l1.1-.5v1z"/>
<path d="M68.8 103.4h.5v4.5h-.5z"/>
<path d="M72.3 166.6l1.1-.5v1z"/>
<path d="M117.3 137.7h.6v4.5h-.6z"/>
<path d="M137 131.1l1.2-.5v1z"/>
<path d="M41.8 94.2l1.1-.5v1z"/>
<path d="M137 117.1l1.2-.5v1z"/>
<path d="M130 105.9h.6v4.6h-.6z"/>
<path d="M246.9 130h.5v4.6h-.5z"/>
<path d="M137 47.2l1.2-.5v1z"/>
<path d="M130 36.1h.6v4.5h-.6z"/>
<path d="M117.3 67.8h.6v4.6h-.6z"/>
<path d="M146.6 165.6h.5v4.6h-.5z"/>
<path d="M155.2 70.4h.5v4.5h-.5z"/>
<path d="M156.7 173l1.2-.5v1z"/>
<path d="M137 61.2l1.2-.5v1z"/>
<path d="M62.7 159.3h.5v4.5h-.5z"/>
<path d="M256.4 137.4l1.2-.5v1z"/>
</g>
<g fill="none" stroke="#008484" stroke-width=".18">
<path d="M210.9 39.6v1M243.3 39.6v1M254.6 39.7l1.2 .4-1.2 .5M255.4 38.3v1M270.6 39.6v1M111 41h1M168.1 47.3h1M210.1 41l1.3 .4-1.3 .4M220.9 41.6l1.3 .4-1.3 .5M221.7 40.2v1M242.5 41l1.3 .4-1.3 .4M269.8 41l1.3 .4-1.3 .4"/>
<path d="M94.5 72.7h1M111 110.8h1M168.1 117.2h1M227.8 135h1M94.5 142.6h1M181.4 141.9h.8l-.4 .5 .4 .1v.5l-.2 .2-.6-.2M43.7 164.2h1M127.5 170.5h1"/>
</g>
<path d="M231.1 58.7h15.3v17.7h-15.3zM163.8 67.6h20.3v22.8h-20.3z" fill="none" stroke="#840000" stroke-width=".41"/>
<path d="M172.7 150.1h1.3v2.5h-1.3z" fill="#840000" stroke="#840000" stroke-width=".25"/>
<g fill="none" stroke="#008400" stroke-width=".18">
<path d="M33 16.8h7.6v3.8M52.1 16.8h-1.3v10.1M40.6 28.2v2.5M44.4 24.4h17.8v2.5M50.8 34.5v2.6M50.8 35.8h7.6v31.8h5.1M62.2 34.5v2.6M62.2 35.8h3.8M73.7 35.8h6.3M76.2 24.4v2.5M76.2 34.5v2.6M87.6 35.8h2.6"/>
<path d="M97.8 35.8h10.1M99.1 35.8v2.5M105.4 26.9h-16.5v8.9M113 26.9h11.5v20.3h-17.8v-6.3h1.2M123.2 38.3h2.5M133.3 38.3h2.6v5.1M163.8 29.5v1.2M163.8 38.3v3.9h1.3M193 24.4h6.4M210.8 28.8v1.9M221.6 29.5v1.9M232.4 24.4v2.5"/>
<path d="M243.2 28.2v2.5M255.3 28.2v1.3M270.5 29.5v1.2M27.9 59.9h6.4v1.3M50.8 44.7v1.3M62.2 44.7v1.3M76.2 44.7v1.3M88.9 57.4h-16.5v10.2M96.5 57.4h12.7v20.3h-20.3v-5.1h2.5M99.1 46v1.2M133.3 54.9h2.6M135.9 51v6.4"/>
<path d="M154.9 47.2h10.2M163.8 47.2v14h-8.9M163.8 53.6h5.1M180.3 44.7h3.8v8.9h-7.6M191.8 44.7h1.2M194.3 57.4v1.3M210.8 46v1.2M221.6 46.6v1.3M232.4 48.5v1.3M243.2 46v.6M255.3 44.7v1.3M270.5 46v1.2"/>
<path d="M34.3 68.8v5.1M38.1 65h1.3M47 65h1.3M71.1 67.6h3.8M82.5 67.6h8.9M83.8 67.6v6.3M106.7 70.1h6.3M135.9 65v5.1h-15.3M144.8 77.7h2.5M152.4 72.6h-6.4v5.1M154.9 77.7h6.4M160 72.6h1.3"/>
<path d="M186.7 75.2h11.4M194.3 67.6h11.4M194.3 66.3v3.8h-7.6M196.8 75.2v1.2M221 67.6h5.1M224.8 61.2h1.3M224.8 71.4h1.3M224.8 73.9h1.3M251.5 61.2h2.5M260.3 76.4v1.3M33 86.6h7.6v3.8M40.6 98v2.6"/>
<path d="M44.4 94.2h17.8v2.6M50.8 94.2v2.6M73.7 86.6h1.2M76.2 94.2v2.6M82.5 86.6h2.6M83.8 81.5v5.1M92.7 86.6h1.3M105.4 96.8h-16.5v8.9M113 96.8h11.5v20.3h-17.8v-6.4h1.2M134.6 82.8h1.3M143.5 82.8h17.8M163.8 99.3v1.3"/>
<path d="M174 93v2.5M176.5 93v1.9h3.2M186.7 80.3h3.8M194.3 84.1h2.5v3.8h-6.3M50.8 105.7h7.6v31.7h5.1M50.8 104.4v2.5M50.8 114.5v1.3M62.2 105.7h3.8M62.2 104.4v2.5M62.2 114.5v1.3M73.7 105.7h6.3M76.2 104.4v2.5"/>
<path d="M76.2 114.5v1.3M87.6 105.7h2.6M97.8 105.7h10.1M99.1 105.7v2.5M99.1 115.8v1.3M123.2 108.2h2.5M133.3 108.2h2.6v5.1M154.9 117.1h10.2M163.8 108.2v3.8h1.3M163.8 117.1v14h-8.9M180.3 114.5h3.8v8.9h-7.6M191.8 114.5h1.2"/>
<path d="M260.3 103.1v1.3M71.1 137.4h3.8M82.5 137.4h8.9M83.8 137.4v6.4M88.9 127.2h-16.5v10.2M96.5 127.2h12.7v20.4h-20.3v-5.1h2.5M106.7 139.9h6.3M133.3 124.7h2.6M135.9 120.9v6.3M135.9 134.9v5h-15.3M163.8 123.4h5.1M214.6 123.4h1.3"/>
<path d="M214.6 134.9h2.6M223.5 123.4h3.8M224.8 123.4v6.4M224.8 134.9v7.6h5.1M234.9 123.4h1.3M242.6 132.3h-2.6v10.2h-2.5M250.2 132.3h5.1M259.1 137.4h2.5M30.5 152.6h1.2M39.4 152.6h3.8M40.6 152.6v6.4M50.8 152.6h1.3"/>
<path d="M73.7 156.5h1.2M82.5 156.5h2.6M83.8 151.4v5.1M92.7 156.5h1.3M114.3 159h1.3M123.2 159h3.8M124.5 159v6.3M134.6 159h1.3M214.6 142.5h2.6M31.7 179.3h1.3M31.7 171.7h1.3M31.7 164.1h1.3"/>
<path d="M40.6 164.1v22.8M40.6 171.7h5.1M58.4 161.5h-2.5v10.2h-2.6M66 161.5h5.1M71.1 170.4v1.3M114.3 178h2.5M114.3 170.4h2.5M124.5 170.4v15.3M124.5 178h5M142.2 167.9h-2.5v10.1h-2.5M149.9 167.9h5.7v1.3M159.4 173h.6"/>
<path d="M31.7 186.9h1.3M114.3 185.7h2.5"/>
</g>
<g fill="#008400" stroke="#008400" stroke-width=".18">
<circle cx="124.5" cy="38.3" r=".46"/>
<circle cx="88.9" cy="105.7" r=".46"/>
<circle cx="99.1" cy="105.7" r=".46"/>
<circle cx="99.1" cy="35.8" r=".46"/>
<circle cx="83.8" cy="67.6" r=".46"/>
<circle cx="163.8" cy="53.6" r=".46"/>
<circle cx="163.8" cy="47.2" r=".46"/>
<circle cx="146" cy="77.7" r=".46"/>
<circle cx="184.1" cy="44.7" r=".46"/>
<circle cx="135.9" cy="54.9" r=".46"/>
<circle cx="163.8" cy="42.2" r=".46"/>
<circle cx="184.1" cy="114.5" r=".46"/>
<circle cx="240" cy="132.3" r=".46"/>
<circle cx="224.8" cy="123.4" r=".46"/>
<circle cx="224.8" cy="142.5" r=".46"/>
<circle cx="224.8" cy="134.9" r=".46"/>
<circle cx="163.8" cy="123.4" r=".46"/>
<circle cx="163.8" cy="112" r=".46"/>
<circle cx="196.8" cy="84.1" r=".46"/>
<circle cx="196.8" cy="75.2" r=".46"/>
<circle cx="194.3" cy="67.6" r=".46"/>
<circle cx="135.9" cy="124.7" r=".46"/>
<circle cx="163.8" cy="117.1" r=".46"/>
<circle cx="124.5" cy="108.2" r=".46"/>
<circle cx="83.8" cy="137.4" r=".46"/>
<circle cx="109.2" cy="139.9" r=".46"/>
<circle cx="83.8" cy="156.5" r=".46"/>
<circle cx="109.2" cy="70.1" r=".46"/>
<circle cx="88.9" cy="35.8" r=".46"/>
<circle cx="76.2" cy="35.8" r=".46"/>
<circle cx="40.6" cy="152.6" r=".46"/>
<circle cx="72.4" cy="137.4" r=".46"/>
<circle cx="76.2" cy="105.7" r=".46"/>
<circle cx="62.2" cy="105.7" r=".46"/>
<circle cx="50.8" cy="94.2" r=".46"/>
<circle cx="50.8" cy="105.7" r=".46"/>
<circle cx="83.8" cy="86.6" r=".46"/>
<circle cx="72.4" cy="67.6" r=".46"/>
<circle cx="50.8" cy="35.8" r=".46"/>
<circle cx="62.2" cy="35.8" r=".46"/>
<circle cx="50.8" cy="24.4" r=".46"/>
<circle cx="124.5" cy="178" r=".46"/>
<circle cx="124.5" cy="170.4" r=".46"/>
<circle cx="124.5" cy="159" r=".46"/>
<circle cx="139.7" cy="167.9" r=".46"/>
<circle cx="40.6" cy="164.1" r=".46"/>
<circle cx="40.6" cy="171.7" r=".46"/>
<circle cx="40.6" cy="179.3" r=".46"/>
<circle cx="55.9" cy="161.5" r=".46"/>
</g>
<use href="#words"/>
</svg>
